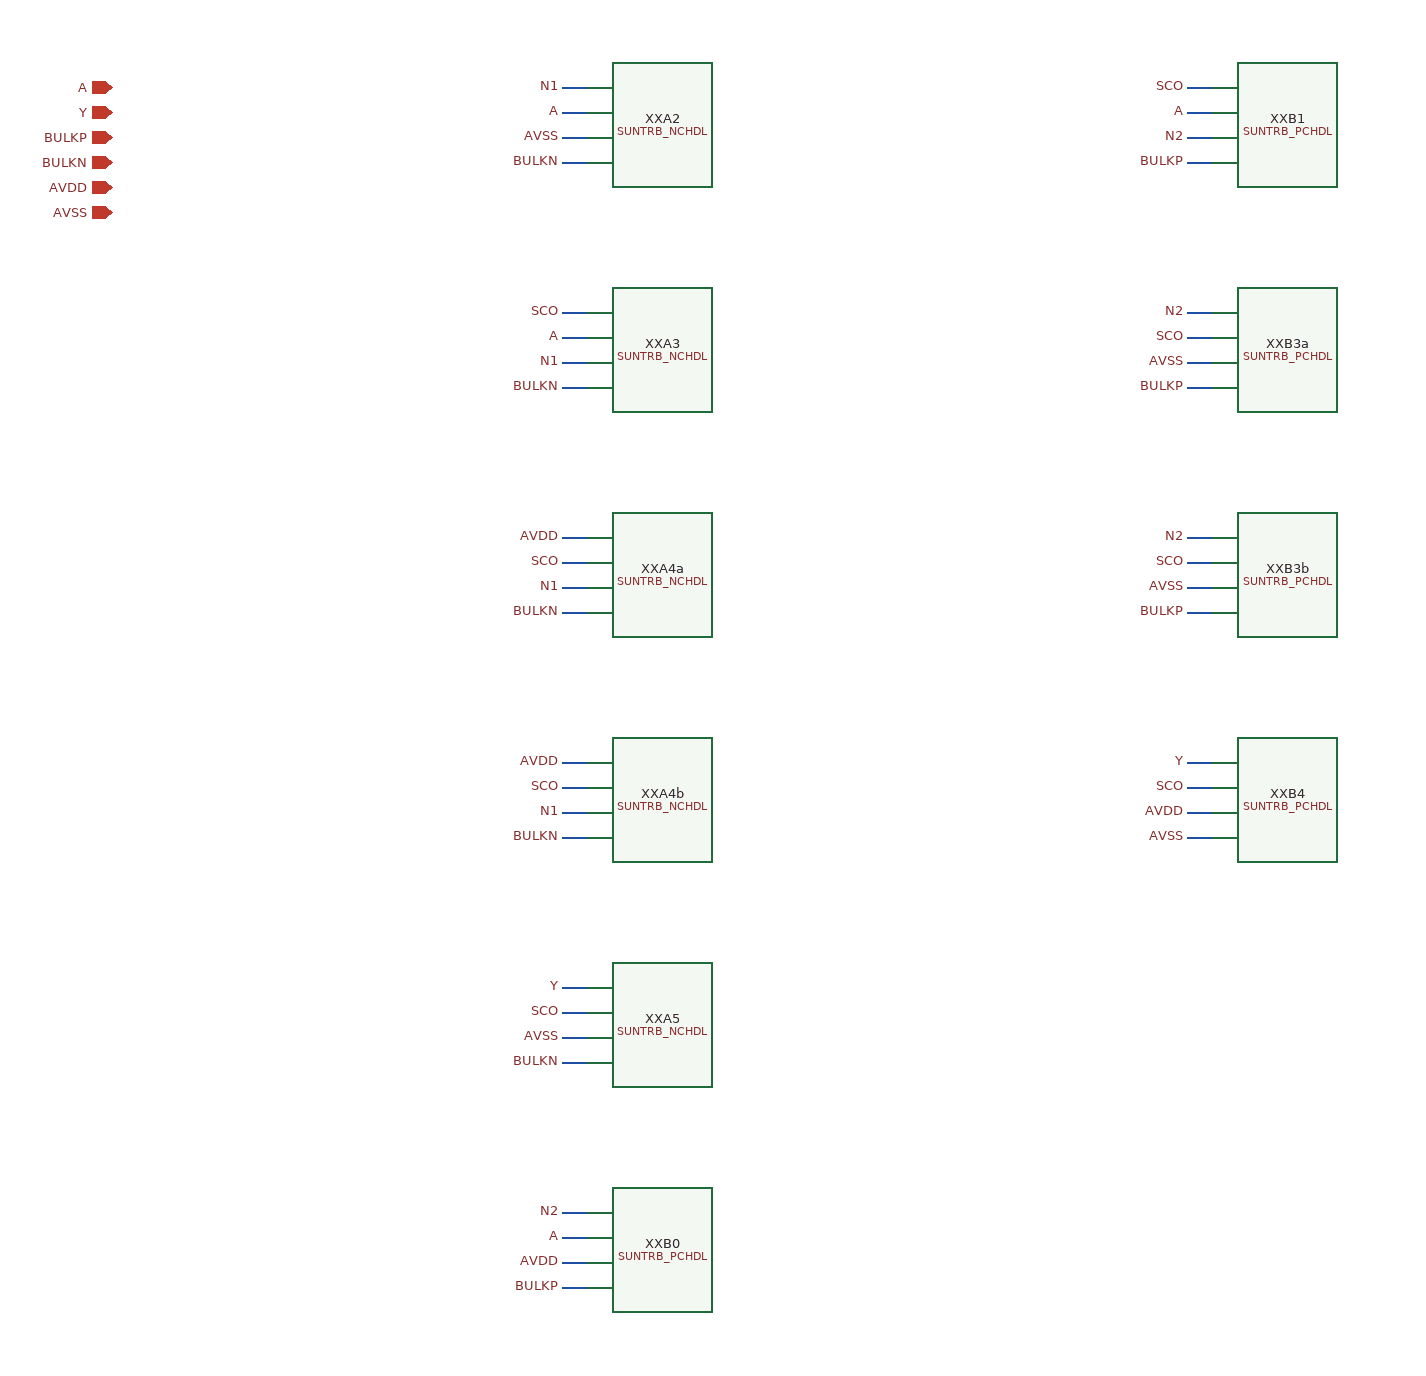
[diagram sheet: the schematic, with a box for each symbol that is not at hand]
v {xschem version=3.0.0 file_version=1.2 }
G {}
K {}
V {}
S {}
E {}
C {devices/iopin.sym} 0 0 0 0{name=p0 lab=A}
C {devices/iopin.sym} 0 20 0 0{name=p1 lab=Y}
C {devices/iopin.sym} 0 40 0 0{name=p2 lab=BULKP}
C {devices/iopin.sym} 0 60 0 0{name=p3 lab=BULKN}
C {devices/iopin.sym} 0 80 0 0{name=p4 lab=AVDD}
C {devices/iopin.sym} 0 100 0 0{name=p5 lab=AVSS}
C {SUN_TRB_SKY130NM/SUNTRB_NCHDL.sym} 400 0 0 0 {name=XXA2}
N 360.0 0.0 380.0 0.0{lab=N1}
C {devices/lab_pin.sym} 360.0 0.0 0 0  {name=l0 sig_type=std_logic lab=N1 }
N 360.0 20.0 380.0 20.0{lab=A}
C {devices/lab_pin.sym} 360.0 20.0 0 0  {name=l1 sig_type=std_logic lab=A }
N 360.0 40.0 380.0 40.0{lab=AVSS}
C {devices/lab_pin.sym} 360.0 40.0 0 0  {name=l2 sig_type=std_logic lab=AVSS }
N 360.0 60.0 380.0 60.0{lab=BULKN}
C {devices/lab_pin.sym} 360.0 60.0 0 0  {name=l3 sig_type=std_logic lab=BULKN }
C {SUN_TRB_SKY130NM/SUNTRB_NCHDL.sym} 400 180.0 0 0 {name=XXA3}
N 360.0 180.0 380.0 180.0{lab=SCO}
C {devices/lab_pin.sym} 360.0 180.0 0 0  {name=l4 sig_type=std_logic lab=SCO }
N 360.0 200.0 380.0 200.0{lab=A}
C {devices/lab_pin.sym} 360.0 200.0 0 0  {name=l5 sig_type=std_logic lab=A }
N 360.0 220.0 380.0 220.0{lab=N1}
C {devices/lab_pin.sym} 360.0 220.0 0 0  {name=l6 sig_type=std_logic lab=N1 }
N 360.0 240.0 380.0 240.0{lab=BULKN}
C {devices/lab_pin.sym} 360.0 240.0 0 0  {name=l7 sig_type=std_logic lab=BULKN }
C {SUN_TRB_SKY130NM/SUNTRB_NCHDL.sym} 400 360.0 0 0 {name=XXA4a}
N 360.0 360.0 380.0 360.0{lab=AVDD}
C {devices/lab_pin.sym} 360.0 360.0 0 0  {name=l8 sig_type=std_logic lab=AVDD }
N 360.0 380.0 380.0 380.0{lab=SCO}
C {devices/lab_pin.sym} 360.0 380.0 0 0  {name=l9 sig_type=std_logic lab=SCO }
N 360.0 400.0 380.0 400.0{lab=N1}
C {devices/lab_pin.sym} 360.0 400.0 0 0  {name=l10 sig_type=std_logic lab=N1 }
N 360.0 420.0 380.0 420.0{lab=BULKN}
C {devices/lab_pin.sym} 360.0 420.0 0 0  {name=l11 sig_type=std_logic lab=BULKN }
C {SUN_TRB_SKY130NM/SUNTRB_NCHDL.sym} 400 540.0 0 0 {name=XXA4b}
N 360.0 540.0 380.0 540.0{lab=AVDD}
C {devices/lab_pin.sym} 360.0 540.0 0 0  {name=l12 sig_type=std_logic lab=AVDD }
N 360.0 560.0 380.0 560.0{lab=SCO}
C {devices/lab_pin.sym} 360.0 560.0 0 0  {name=l13 sig_type=std_logic lab=SCO }
N 360.0 580.0 380.0 580.0{lab=N1}
C {devices/lab_pin.sym} 360.0 580.0 0 0  {name=l14 sig_type=std_logic lab=N1 }
N 360.0 600.0 380.0 600.0{lab=BULKN}
C {devices/lab_pin.sym} 360.0 600.0 0 0  {name=l15 sig_type=std_logic lab=BULKN }
C {SUN_TRB_SKY130NM/SUNTRB_NCHDL.sym} 400 720.0 0 0 {name=XXA5}
N 360.0 720.0 380.0 720.0{lab=Y}
C {devices/lab_pin.sym} 360.0 720.0 0 0  {name=l16 sig_type=std_logic lab=Y }
N 360.0 740.0 380.0 740.0{lab=SCO}
C {devices/lab_pin.sym} 360.0 740.0 0 0  {name=l17 sig_type=std_logic lab=SCO }
N 360.0 760.0 380.0 760.0{lab=AVSS}
C {devices/lab_pin.sym} 360.0 760.0 0 0  {name=l18 sig_type=std_logic lab=AVSS }
N 360.0 780.0 380.0 780.0{lab=BULKN}
C {devices/lab_pin.sym} 360.0 780.0 0 0  {name=l19 sig_type=std_logic lab=BULKN }
C {SUN_TRB_SKY130NM/SUNTRB_PCHDL.sym} 400 900.0 0 0 {name=XXB0}
N 360.0 900.0 380.0 900.0{lab=N2}
C {devices/lab_pin.sym} 360.0 900.0 0 0  {name=l20 sig_type=std_logic lab=N2 }
N 360.0 920.0 380.0 920.0{lab=A}
C {devices/lab_pin.sym} 360.0 920.0 0 0  {name=l21 sig_type=std_logic lab=A }
N 360.0 940.0 380.0 940.0{lab=AVDD}
C {devices/lab_pin.sym} 360.0 940.0 0 0  {name=l22 sig_type=std_logic lab=AVDD }
N 360.0 960.0 380.0 960.0{lab=BULKP}
C {devices/lab_pin.sym} 360.0 960.0 0 0  {name=l23 sig_type=std_logic lab=BULKP }
C {SUN_TRB_SKY130NM/SUNTRB_PCHDL.sym} 900 0 0 0 {name=XXB1}
N 860.0 0.0 880.0 0.0{lab=SCO}
C {devices/lab_pin.sym} 860.0 0.0 0 0  {name=l24 sig_type=std_logic lab=SCO }
N 860.0 20.0 880.0 20.0{lab=A}
C {devices/lab_pin.sym} 860.0 20.0 0 0  {name=l25 sig_type=std_logic lab=A }
N 860.0 40.0 880.0 40.0{lab=N2}
C {devices/lab_pin.sym} 860.0 40.0 0 0  {name=l26 sig_type=std_logic lab=N2 }
N 860.0 60.0 880.0 60.0{lab=BULKP}
C {devices/lab_pin.sym} 860.0 60.0 0 0  {name=l27 sig_type=std_logic lab=BULKP }
C {SUN_TRB_SKY130NM/SUNTRB_PCHDL.sym} 900 180.0 0 0 {name=XXB3a}
N 860.0 180.0 880.0 180.0{lab=N2}
C {devices/lab_pin.sym} 860.0 180.0 0 0  {name=l28 sig_type=std_logic lab=N2 }
N 860.0 200.0 880.0 200.0{lab=SCO}
C {devices/lab_pin.sym} 860.0 200.0 0 0  {name=l29 sig_type=std_logic lab=SCO }
N 860.0 220.0 880.0 220.0{lab=AVSS}
C {devices/lab_pin.sym} 860.0 220.0 0 0  {name=l30 sig_type=std_logic lab=AVSS }
N 860.0 240.0 880.0 240.0{lab=BULKP}
C {devices/lab_pin.sym} 860.0 240.0 0 0  {name=l31 sig_type=std_logic lab=BULKP }
C {SUN_TRB_SKY130NM/SUNTRB_PCHDL.sym} 900 360.0 0 0 {name=XXB3b}
N 860.0 360.0 880.0 360.0{lab=N2}
C {devices/lab_pin.sym} 860.0 360.0 0 0  {name=l32 sig_type=std_logic lab=N2 }
N 860.0 380.0 880.0 380.0{lab=SCO}
C {devices/lab_pin.sym} 860.0 380.0 0 0  {name=l33 sig_type=std_logic lab=SCO }
N 860.0 400.0 880.0 400.0{lab=AVSS}
C {devices/lab_pin.sym} 860.0 400.0 0 0  {name=l34 sig_type=std_logic lab=AVSS }
N 860.0 420.0 880.0 420.0{lab=BULKP}
C {devices/lab_pin.sym} 860.0 420.0 0 0  {name=l35 sig_type=std_logic lab=BULKP }
C {SUN_TRB_SKY130NM/SUNTRB_PCHDL.sym} 900 540.0 0 0 {name=XXB4}
N 860.0 540.0 880.0 540.0{lab=Y}
C {devices/lab_pin.sym} 860.0 540.0 0 0  {name=l36 sig_type=std_logic lab=Y }
N 860.0 560.0 880.0 560.0{lab=SCO}
C {devices/lab_pin.sym} 860.0 560.0 0 0  {name=l37 sig_type=std_logic lab=SCO }
N 860.0 580.0 880.0 580.0{lab=AVDD}
C {devices/lab_pin.sym} 860.0 580.0 0 0  {name=l38 sig_type=std_logic lab=AVDD }
N 860.0 600.0 880.0 600.0{lab=AVSS}
C {devices/lab_pin.sym} 860.0 600.0 0 0  {name=l39 sig_type=std_logic lab=AVSS }
